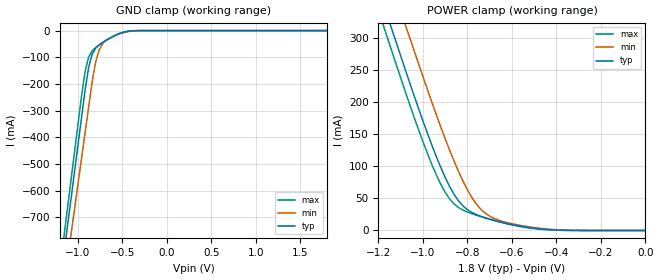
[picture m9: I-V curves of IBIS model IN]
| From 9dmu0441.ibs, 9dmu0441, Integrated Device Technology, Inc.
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|   Model IN
[Model]  IN
Model_type Input
Polarity   Non-Inverting
Enable   Active-High
Vinl =   0.4000V
Vinh =   0.9000V
C_comp   1.1000pF   1.0000pF   1.2000pF
[Temperature Range]   25.0000   75.0000   0.0
[Voltage Range]   1.8000V   1.6200V   1.9800V
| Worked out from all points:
|   GND clamp passes 1 mA (typ) near -0.39 V on its own axis
|   POWER clamp passes 1 mA (typ) near -0.42 V on its own axis
[GND_clamp]
|Voltage   I(typ)   I(min)   I(max)
-1.8V     -2.493A    -2.51A     -2.486A
-1.16V    -842mA     -962.5mA   -778.8mA
-1.12V    -738.9mA   -865.9mA   -672.1mA
-1.08V    -635.8mA   -769.3mA   -565.4mA
-1.04V    -532.7mA   -672.7mA   -458.7mA
-920mV    -223.7mA   -383.2mA   -153.9mA
-880mV    -138.6mA   -286.7mA   -99.22mA
-840mV    -88.36mA   -191.1mA   -75.31mA
-800mV    -65.22mA   -115.9mA   -63.5mA
-720mV    -43.79mA   -48.15mA   -44.92mA
-360mV    -441.1uA   -818uA     -302.1uA
1.8V      1.816nA    7.019uA    5.116uA
[POWER_clamp]
|Voltage   I(typ)   I(min)   I(max)
-1.8V     1A         1.055A     973.2mA
-1.18V    355.2mA    423.3mA    321.5mA
-1.14V    313.6mA    382.5mA    279.5mA
-1.08V    251.2mA    321.3mA    217mA
-1.06V    230.6mA    300.9mA    196.6mA
-980mV    151.5mA    219.6mA    120.1mA
-900mV    82.63mA    142.8mA    59.34mA
-820mV    38.17mA    76.72mA    31.7mA
-760mV    24.8mA     41.15mA    23.72mA
-720mV    19.84mA    26.87mA    19.38mA
-460mV    2.018mA    2.851mA    1.623mA
0V        1.816nA    21.37nA    894.6pA
